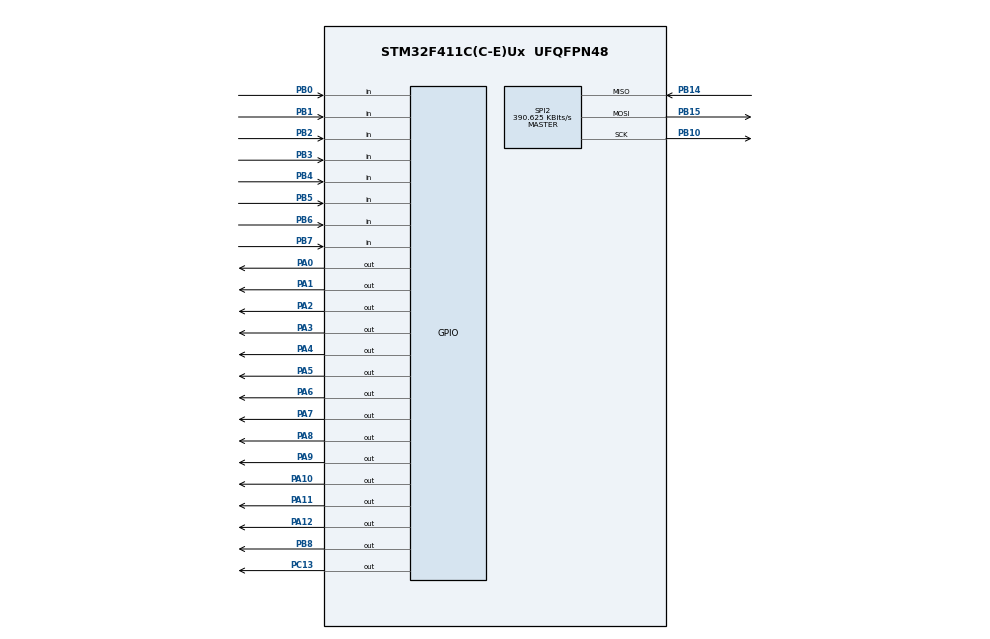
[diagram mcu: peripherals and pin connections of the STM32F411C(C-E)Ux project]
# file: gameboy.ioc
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FATFS._USE_LFN=1
FATFS._USE_STRFUNC=1
Mcu.Family=STM32F4
Mcu.Name=STM32F411C(C-E)Ux
Mcu.Package=UFQFPN48
NVIC.PriorityGroup=NVIC_PRIORITYGROUP_4
PA0-WKUP.Signal=GPIO_Output
PA1.Signal=GPIO_Output
PA10.Signal=GPIO_Output
PA11.Signal=GPIO_Output
PA12.Signal=GPIO_Output
PA2.Signal=GPIO_Output
PA3.Signal=GPIO_Output
PA4.Signal=GPIO_Output
PA5.Signal=GPIO_Output
PA6.Signal=GPIO_Output
PA7.Signal=GPIO_Output
PA8.Signal=GPIO_Output
PA9.Signal=GPIO_Output
PB0.Signal=GPIO_Input
PB1.Signal=GPIO_Input
PB10.Mode=Full_Duplex_Master
PB10.Signal=SPI2_SCK
PB14.Mode=Full_Duplex_Master
PB14.Signal=SPI2_MISO
PB15.Mode=Full_Duplex_Master
PB15.Signal=SPI2_MOSI
PB2.Signal=GPIO_Input
PB3.Signal=GPIO_Input
PB4.Signal=GPIO_Input
PB5.Signal=GPIO_Input
PB6.Signal=GPIO_Input
PB7.Signal=GPIO_Input
PB8.Signal=GPIO_Output
PC13-ANTI_TAMP.Signal=GPIO_Output
ProjectManager.HeapSize=0x200
ProjectManager.StackSize=0x400
ProjectManager.TargetToolchain=Makefile
RCC.48MHZClocksFreq_Value=50000000
RCC.AHBFreq_Value=100000000
RCC.APB1CLKDivider=RCC_HCLK_DIV2
RCC.APB1Freq_Value=50000000
RCC.APB1TimFreq_Value=100000000
RCC.APB2Freq_Value=100000000
RCC.APB2TimFreq_Value=100000000
RCC.CortexFreq_Value=100000000
RCC.HCLKFreq_Value=100000000
RCC.HSE_VALUE=25000000
RCC.HSI_VALUE=16000000
RCC.LSE_VALUE=32768
RCC.PLLM=8
RCC.PLLN=100
RCC.SYSCLKFreq_VALUE=100000000
RCC.SYSCLKSource=RCC_SYSCLKSOURCE_PLLCLK
RCC.VCOOutputFreq_Value=200000000
RTC.Date=2
RTC.Format=RTC_FORMAT_BIN
RTC.Hours=23
RTC.Minutes=34
RTC.Month=RTC_MONTH_AUGUST
RTC.WeekDay=RTC_WEEKDAY_TUESDAY
RTC.Year=22
SPI2.BaudRatePrescaler=SPI_BAUDRATEPRESCALER_128
SPI2.CalculateBaudRate=390.625 KBits/s
SPI2.Direction=SPI_DIRECTION_2LINES
SPI2.Mode=SPI_MODE_MASTER
SPI2.VirtualType=VM_MASTER
VP_FATFS_VS_Generic.Mode=User_defined
VP_RTC_VS_RTC_Activate.Mode=RTC_Enabled
VP_RTC_VS_RTC_Calendar.Mode=RTC_Calendar
board=custom

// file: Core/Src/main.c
/* USER CODE BEGIN Header */
/**
 ******************************************************************************
 * @file           : main.c
 * @brief          : Main program body
 ******************************************************************************
 * @attention
 *
 * Copyright (c) 2022 STMicroelectronics.
 * All rights reserved.
 *
 * This software is licensed under terms that can be found in the LICENSE file
 * in the root directory of this software component.
 * If no LICENSE file comes with this software, it is provided AS-IS.
 *
 ******************************************************************************
 */
/* USER CODE END Header */
#include "main.h"
#include "fatfs.h"

/* USER CODE BEGIN Includes */
#include "config.h"
#include "display/ili9341.h"
#include "emulator/emulator_hooks.h"
#include "gamepad/gamepad.h"
#include "gui/game_selector.h"
#include <stdio.h>
#include <time.h>

/* USER CODE END Includes */

RTC_HandleTypeDef hrtc;

SPI_HandleTypeDef hspi2;

void SystemClock_Config(void);
static void MX_GPIO_Init(void);
static void MX_RTC_Init(void);
static void MX_SPI2_Init(void);

int main(void) {

  /* MCU Configuration--------------------------------------------------------*/

  /* Reset of all peripherals, Initializes the Flash interface and the Systick.
   */
  HAL_Init();

  /* Configure the system clock */
  SystemClock_Config();

  /* Initialize all configured peripherals */
  MX_GPIO_Init();
  MX_RTC_Init();
  MX_SPI2_Init();
  MX_FATFS_Init();
  /* USER CODE BEGIN 2 */

  InitializeGamepadPins();

  struct ILI9341_t lcd;
  ILI9341_Init(&lcd, (struct ILI9341_Pin_t){LCD_D7},
               (struct ILI9341_Pin_t){LCD_D6}, (struct ILI9341_Pin_t){LCD_D5},
               (struct ILI9341_Pin_t){LCD_D4}, (struct ILI9341_Pin_t){LCD_D3},
               (struct ILI9341_Pin_t){LCD_D2}, (struct ILI9341_Pin_t){LCD_D1},
               (struct ILI9341_Pin_t){LCD_D0},

               (struct ILI9341_Pin_t){LCD_RESET},
               (struct ILI9341_Pin_t){LCD_CS}, (struct ILI9341_Pin_t){LCD_RS},
               (struct ILI9341_Pin_t){LCD_WR}, (struct ILI9341_Pin_t){LCD_RD});
  ILI9341_SendInitializationSequence(&lcd);
  ILI9341_SetOrientation(&lcd, HORIZONTAL);
  ILI9341_FillScreen(&lcd, ILI9341_RgbTo565(50, 50, 50));

  FATFS fs;
  FRESULT res;

  HAL_Delay(3500);

  for (int i = 0; i < 10; i++) {
    res = f_mount(&fs, "", 1);
    if (res == FR_OK) {
      break;
    }

    HAL_Delay(500);
  }
  if (res != FR_OK)
    HaltAndShowErrorScreen(&lcd, "  Failed to read", " from the SD card");

  struct GameChoice choice;
  GameSelectionMenu(&lcd, &choice);

  RTC_TimeTypeDef time;
  RTC_DateTypeDef date;
  HAL_RTC_GetTime(&hrtc, &time, RTC_FORMAT_BIN);
  HAL_RTC_GetDate(&hrtc, &date, RTC_FORMAT_BIN);
  StartEmulator(&lcd, &choice,
                (struct tm){.tm_sec = time.Seconds,
                            .tm_min = time.Minutes,
                            .tm_hour = time.Hours,
                            .tm_mday = date.Date,
                            .tm_mon = date.Month,
                            .tm_year = date.Year,
                            .tm_wday = date.WeekDay,
                            .tm_yday = 0,
                            .tm_isdst = 0});
  /* USER CODE END 2 */

  /* Infinite loop */
  while (1) {

  }
}

void SystemClock_Config(void) {
  RCC_OscInitTypeDef RCC_OscInitStruct = {0};
  RCC_ClkInitTypeDef RCC_ClkInitStruct = {0};

  /** Configure the main internal regulator output voltage
   */
  __HAL_RCC_PWR_CLK_ENABLE();
  __HAL_PWR_VOLTAGESCALING_CONFIG(PWR_REGULATOR_VOLTAGE_SCALE1);

  /** Initializes the RCC Oscillators according to the specified parameters
   * in the RCC_OscInitTypeDef structure.
   */
  RCC_OscInitStruct.OscillatorType =
      RCC_OSCILLATORTYPE_HSI | RCC_OSCILLATORTYPE_LSI;
  RCC_OscInitStruct.HSIState = RCC_HSI_ON;
  RCC_OscInitStruct.HSICalibrationValue = RCC_HSICALIBRATION_DEFAULT;
  RCC_OscInitStruct.LSIState = RCC_LSI_ON;
  RCC_OscInitStruct.PLL.PLLState = RCC_PLL_ON;
  RCC_OscInitStruct.PLL.PLLSource = RCC_PLLSOURCE_HSI;
  RCC_OscInitStruct.PLL.PLLM = 8;
  RCC_OscInitStruct.PLL.PLLN = 140;
  RCC_OscInitStruct.PLL.PLLP = RCC_PLLP_DIV2;
  RCC_OscInitStruct.PLL.PLLQ = 4;
  if (HAL_RCC_OscConfig(&RCC_OscInitStruct) != HAL_OK) {
    Error_Handler();
  }

  /** Initializes the CPU, AHB and APB buses clocks
   */
  RCC_ClkInitStruct.ClockType = RCC_CLOCKTYPE_HCLK | RCC_CLOCKTYPE_SYSCLK |
                                RCC_CLOCKTYPE_PCLK1 | RCC_CLOCKTYPE_PCLK2;
  RCC_ClkInitStruct.SYSCLKSource = RCC_SYSCLKSOURCE_PLLCLK;
  RCC_ClkInitStruct.AHBCLKDivider = RCC_SYSCLK_DIV1;
  RCC_ClkInitStruct.APB1CLKDivider = RCC_HCLK_DIV4;
  RCC_ClkInitStruct.APB2CLKDivider = RCC_HCLK_DIV1;

  if (HAL_RCC_ClockConfig(&RCC_ClkInitStruct, FLASH_LATENCY_3) != HAL_OK) {
    Error_Handler();
  }
}

static void MX_RTC_Init(void) {

  RTC_TimeTypeDef sTime = {0};
  RTC_DateTypeDef sDate = {0};

  /** Initialize RTC Only
   */
  hrtc.Instance = RTC;
  hrtc.Init.HourFormat = RTC_HOURFORMAT_24;
  hrtc.Init.AsynchPrediv = 127;
  hrtc.Init.SynchPrediv = 255;
  hrtc.Init.OutPut = RTC_OUTPUT_DISABLE;
  hrtc.Init.OutPutPolarity = RTC_OUTPUT_POLARITY_HIGH;
  hrtc.Init.OutPutType = RTC_OUTPUT_TYPE_OPENDRAIN;
  if (HAL_RTC_Init(&hrtc) != HAL_OK) {
    Error_Handler();
  }

  /** Initialize RTC and set the Time and Date
   */
  sTime.Hours = 23;
  sTime.Minutes = 34;
  sTime.Seconds = 0;
  sTime.DayLightSaving = RTC_DAYLIGHTSAVING_NONE;
  sTime.StoreOperation = RTC_STOREOPERATION_RESET;
  if (HAL_RTC_SetTime(&hrtc, &sTime, RTC_FORMAT_BIN) != HAL_OK) {
    Error_Handler();
  }
  sDate.WeekDay = RTC_WEEKDAY_TUESDAY;
  sDate.Month = RTC_MONTH_AUGUST;
  sDate.Date = 2;
  sDate.Year = 22;

  if (HAL_RTC_SetDate(&hrtc, &sDate, RTC_FORMAT_BIN) != HAL_OK) {
    Error_Handler();
  }
}

static void MX_SPI2_Init(void) {

  /* SPI2 parameter configuration*/
  hspi2.Instance = SPI2;
  hspi2.Init.Mode = SPI_MODE_MASTER;
  hspi2.Init.Direction = SPI_DIRECTION_2LINES;
  hspi2.Init.DataSize = SPI_DATASIZE_8BIT;
  hspi2.Init.CLKPolarity = SPI_POLARITY_LOW;
  hspi2.Init.CLKPhase = SPI_PHASE_1EDGE;
  hspi2.Init.NSS = SPI_NSS_SOFT;
  hspi2.Init.BaudRatePrescaler = SPI_BAUDRATEPRESCALER_64;
  hspi2.Init.FirstBit = SPI_FIRSTBIT_MSB;
  hspi2.Init.TIMode = SPI_TIMODE_DISABLE;
  hspi2.Init.CRCCalculation = SPI_CRCCALCULATION_DISABLE;
  hspi2.Init.CRCPolynomial = 10;
  if (HAL_SPI_Init(&hspi2) != HAL_OK) {
    Error_Handler();
  }
}

static void MX_GPIO_Init(void) {
  GPIO_InitTypeDef GPIO_InitStruct = {0};

  /* GPIO Ports Clock Enable */
  __HAL_RCC_GPIOC_CLK_ENABLE();
  __HAL_RCC_GPIOA_CLK_ENABLE();
  __HAL_RCC_GPIOB_CLK_ENABLE();

  /*Configure GPIO pin Output Level */
  HAL_GPIO_WritePin(GPIOC, GPIO_PIN_13, GPIO_PIN_RESET);

  /*Configure GPIO pin Output Level */
  HAL_GPIO_WritePin(GPIOA,
                    GPIO_PIN_0 | GPIO_PIN_1 | GPIO_PIN_2 | GPIO_PIN_3 |
                        GPIO_PIN_4 | GPIO_PIN_5 | GPIO_PIN_6 | GPIO_PIN_7 |
                        GPIO_PIN_8 | GPIO_PIN_9 | GPIO_PIN_10 | GPIO_PIN_11 |
                        GPIO_PIN_12,
                    GPIO_PIN_RESET);

  /*Configure GPIO pin Output Level */
  HAL_GPIO_WritePin(GPIOB, GPIO_PIN_8, GPIO_PIN_RESET);

  /*Configure GPIO pin : PC13 */
  GPIO_InitStruct.Pin = GPIO_PIN_13;
  GPIO_InitStruct.Mode = GPIO_MODE_OUTPUT_PP;
  GPIO_InitStruct.Pull = GPIO_NOPULL;
  GPIO_InitStruct.Speed = GPIO_SPEED_FREQ_LOW;
  HAL_GPIO_Init(GPIOC, &GPIO_InitStruct);

  /*Configure GPIO pins : PA0 PA1 PA2 PA3
                           PA4 PA5 PA6 PA7
                           PA8 PA9 PA10 PA11
                           PA12 */
  GPIO_InitStruct.Pin = GPIO_PIN_0 | GPIO_PIN_1 | GPIO_PIN_2 | GPIO_PIN_3 |
                        GPIO_PIN_4 | GPIO_PIN_5 | GPIO_PIN_6 | GPIO_PIN_7 |
                        GPIO_PIN_8 | GPIO_PIN_9 | GPIO_PIN_10 | GPIO_PIN_11 |
                        GPIO_PIN_12;
  GPIO_InitStruct.Mode = GPIO_MODE_OUTPUT_PP;
  GPIO_InitStruct.Pull = GPIO_NOPULL;
  GPIO_InitStruct.Speed = GPIO_SPEED_FREQ_LOW;
  HAL_GPIO_Init(GPIOA, &GPIO_InitStruct);

  /*Configure GPIO pins : PB0 PB1 PB2 PB3
                           PB4 PB5 PB6 PB7 */
  GPIO_InitStruct.Pin = GPIO_PIN_0 | GPIO_PIN_1 | GPIO_PIN_2 | GPIO_PIN_3 |
                        GPIO_PIN_4 | GPIO_PIN_5 | GPIO_PIN_6 | GPIO_PIN_7;
  GPIO_InitStruct.Mode = GPIO_MODE_INPUT;
  GPIO_InitStruct.Pull = GPIO_NOPULL;
  HAL_GPIO_Init(GPIOB, &GPIO_InitStruct);

  /*Configure GPIO pin : PB8 */
  GPIO_InitStruct.Pin = GPIO_PIN_8;
  GPIO_InitStruct.Mode = GPIO_MODE_OUTPUT_PP;
  GPIO_InitStruct.Pull = GPIO_NOPULL;
  GPIO_InitStruct.Speed = GPIO_SPEED_FREQ_LOW;
  HAL_GPIO_Init(GPIOB, &GPIO_InitStruct);
}

void Error_Handler(void) {
  __disable_irq();
  while (1) {
  }
}

#ifdef USE_FULL_ASSERT
/**
 * @brief  Reports the name of the source file and the source line number
 *         where the assert_param error has occurred.
 * @param  file: pointer to the source file name
 * @param  line: assert_param error line source number
 * @retval None
 */
void assert_failed(uint8_t *file, uint32_t line) {
  /* USER CODE BEGIN 6 */
  /* User can add his own implementation to report the file name and line
     number, ex: printf("Wrong parameters value: file %s on line %d\r\n", file,
     line) */
  /* USER CODE END 6 */
}
#endif /* USE_FULL_ASSERT */
